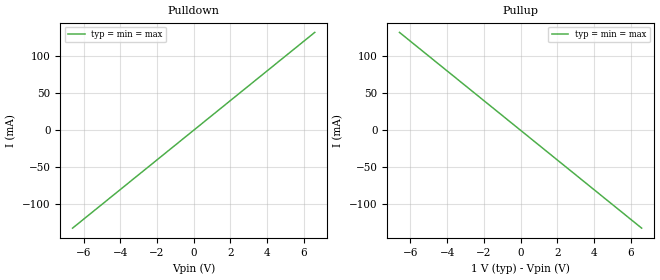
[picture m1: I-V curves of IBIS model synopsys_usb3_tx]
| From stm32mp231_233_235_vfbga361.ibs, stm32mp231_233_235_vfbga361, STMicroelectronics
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[Model] synopsys_usb3_tx
Model_type Output
C_comp 1.69p   1.72p   1.86p
Cref = 0
Vref = 0.5
Rref = 50
Vmeas = 0.5
[Temperature_Range] 25 125 -40
[Voltage Range] 1.0 1.0 1.0
[Algorithmic Model]
Executable Linux_GCC_64 synopsys_usb3_tx_ami_x64.so synopsys_usb3_tx_ami.ami
Executable Windows_cl_64 synopsys_usb3_tx_ami_x64.dll synopsys_usb3_tx_ami.ami
Executable Windows_cl_32 synopsys_usb3_tx_ami.dll synopsys_usb3_tx_ami.ami
[End Algorithmic Model]
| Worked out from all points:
|   slope of the pulldown table from 0 to 0.15 V, typ, clamps not added: 50 ohm
|   slope of the pullup table from 0 to 0.15 V, typ, clamps not added: 50 ohm
[Pulldown]
-6.6V     -132mA     -132mA     -132mA
0V        0A         0A         0A
6.6V      132mA      132mA      132mA
[Pullup]
-6.6V     132mA      132mA      132mA
0V        0A         0A         0A
6.6V      -132mA     -132mA     -132mA
[GND Clamp]
-6.6V     0A         0A         0A
0V        0A         0A         0A
6.6V      0A         0A         0A
[Power Clamp]
-6.6V     0A         0A         0A
0V        0A         0A         0A
6.6V      0A         0A         0A
[Ramp]
dV/dt_r 0.3/1.25p 0.3/1.25p 0.3/1.25p
dV/dt_f 0.3/1.25p 0.3/1.25p 0.3/1.25p
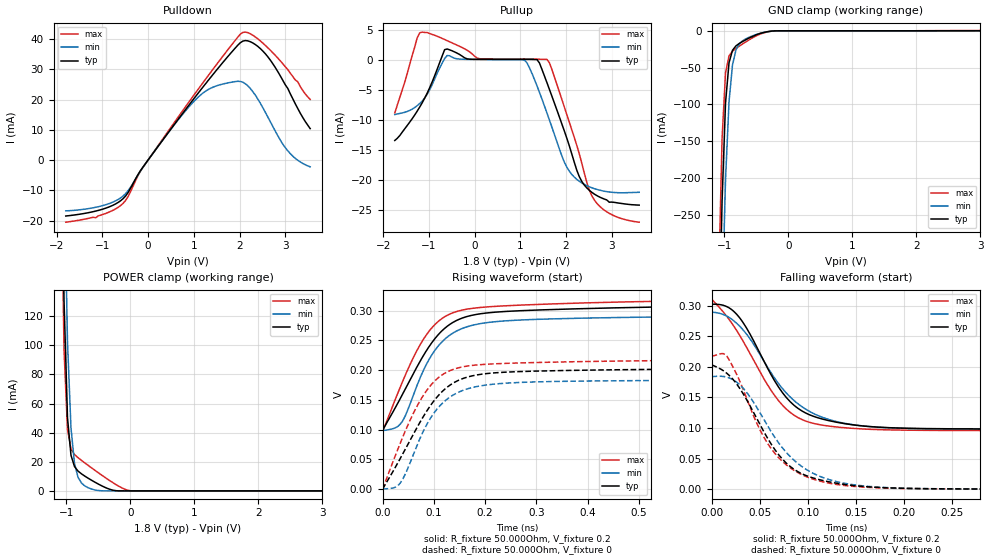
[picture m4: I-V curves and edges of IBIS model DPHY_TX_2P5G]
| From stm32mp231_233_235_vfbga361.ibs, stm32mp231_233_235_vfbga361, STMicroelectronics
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[Model] DPHY_TX_2P5G
Model_type   Output
Polarity   Non-Inverting
Enable   Active-High
C_comp 1.4pF   1.37pF   1.41pF
| This model is not intended for timing simulations.
| Warnings about Cref, Vref & Rref can be ignored
[Temperature Range]   25.000   -40.000   125.000
[Voltage Range]   1.800V   1.516V   2.030V
[GND Clamp Reference]   0.00V   0.00V   0.00V
[Pulldown Reference]   0.00V   0.00V   0.00V
[POWER Clamp Reference]   1.800V   1.516V   2.030V
[Pullup Reference]   1.800V   1.516V   2.030V
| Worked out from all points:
|   slope of the pulldown table from 0 to 0.27 V, typ, clamps not added: 48.6 ohm
|   slope of the pullup table from 0 to 0.27 V, typ, clamps not added: 40.7 kohm
|   GND clamp passes 1 mA (typ) near -0.31 V on its own axis
|   POWER clamp passes 1 mA (typ) near -0.31 V on its own axis
|   rising waveform, R_fixture 50.000Ohm, V_fixture 0.2: 20-80 % time 90.4ps typ, 71.9ps min, 79.7ps max; typ from 0.099 V to 0.31 V
|   rising waveform, R_fixture 50.000Ohm, V_fixture 0: 20-80 % time 87ps typ, 69.4ps min, 74.4ps max; typ from 0 V to 0.203 V
|   falling waveform, R_fixture 50.000Ohm, V_fixture 0.2: 20-80 % time 47.3ps typ, 55.3ps min, 50.3ps max; typ from 0.302 V to 0.098 V
|   falling waveform, R_fixture 50.000Ohm, V_fixture 0: 20-80 % time 48.9ps typ, 52.6ps min, 45ps max; typ from 0.203 V to 0 V
[GND Clamp]
-1.8V     -4.042A    -4.073A    -4.034A
-1.091V   -451.6mA   -607.8mA   -348.2mA
-1.036V   -231.6mA   -376.3mA   -146.6mA
-981.8mV  -97.78mA   -201.9mA   -57.02mA
-927.3mV  -43.35mA   -96.27mA   -34.12mA
-872.7mV  -26.43mA   -46.13mA   -27.69mA
-818.2mV  -20.42mA   -25.76mA   -23.97mA
-763.6mV  -17.02mA   -17.38mA   -20.69mA
-654.5mV  -11.72mA   -10.47mA   -14.49mA
-436.4mV  -3.482mA   -3.303mA   -4.29mA
-218.2mV  -146.9uA   -265.1uA   -132uA
3.545V    426.1nA    2.473uA    648.9uA
[Power Clamp]
-1.745V   4.178A     4.144A     4.305A
-1.091V   310.6mA    421.8mA    251.8mA
-1.036V   130.9mA    223.5mA    97.01mA
-981.8mV  50.29mA    102.3mA    42.42mA
-927.3mV  24.5mA     43.3mA     28.87mA
-872.7mV  16.75mA    18.99mA    25.02mA
-818.2mV  13.67mA    9.453mA    22.85mA
-709.1mV  10.1mA     3.359mA    19.17mA
-545.5mV  5.79mA     575.5uA    13.9mA
-327.3mV  1.19mA     3.793uA    7.229mA
-3uV      9.747nA    10.82nA    94.99uA
3.6V      -1.243uA   -14.78uA   -237.3nA
[Pulldown]
-1.8V     -18.49mA   -16.79mA   -20.54mA
-1.145V   -16.87mA   -15.61mA   -19.07mA
-545.5mV  -12.76mA   -11.88mA   -14.3mA
-163.6mV  -3.435mA   -3.542mA   -3.617mA
600mV     12.28mA    12.18mA    12.96mA
1.091V    22.02mA    20.73mA    23.3mA
1.527V    30.28mA    24.68mA    32.17mA
2.073V    39.32mA    25.73mA    42.18mA
2.291V    38.7mA     22.63mA    41.27mA
2.618V    34.15mA    14.25mA    37.13mA
3.055V    23.7mA     3.064mA    29.91mA
3.545V    10.4mA     -2.252mA   20.05mA
[Pullup]
-1.745V   -13.43mA   -9.108mA   -8.84mA
-1.2V     -7.861mA   -7.271mA   4.52mA
-654.5mV  1.717mA    221.3uA    3.412mA
109.1mV   108.7uA    79.91uA    207.6uA
1.091V    102.7uA    -16.32uA   159.1uA
1.364V    71.88uA    -4.288mA   132.1uA
1.582V    -3.769mA   -8.826mA   89.18uA
2.018V    -13.07mA   -17.9mA    -9.136mA
2.291V    -19.47mA   -20.24mA   -15.68mA
2.564V    -22.08mA   -21.32mA   -22.65mA
2.945V    -23.73mA   -22.02mA   -25.58mA
3.6V      -24.21mA   -22.07mA   -27.06mA
[Ramp]
R_load=50.000Ohm
dV/dt_r   120.00mV/52.400ps  113.564mV/80.000ps  130.791mV/52.000ps
dV/dt_f   120.00mV/46.300ps  112.106mV/62.000ps  129.869mV/46.000ps
[Rising waveform]
R_fixture=50.000Ohm
V_fixture=0.2
0s        98.93mV    98.23mV    96.1mV
24ps      135.4mV    102.7mV    148.9mV
38ps      157.8mV    113.1mV    178.6mV
60ps      194mV      157.8mV    221mV
80ps      225mV      200.1mV    252.3mV
112ps     262.8mV    244mV      284.2mV
150ps     285.7mV    268mV      299.8mV
206ps     296.3mV    280.1mV    306.3mV
308ps     301.1mV    285.5mV    310.5mV
1ns       310.1mV    291.9mV    319.4mV
[Rising waveform]
R_fixture=50.000Ohm
V_fixture=0
0s        -153uV     -19.38uV   -161.4uV
24ps      35.19mV    2.763mV    54.32mV
36ps      53.77mV    12.09mV    80.4mV
58ps      89.01mV    53.64mV    123.7mV
78ps      119.8mV    94.7mV     155.5mV
110ps     158.4mV    138.4mV    188mV
148ps     182.8mV    162.8mV    203.9mV
202ps     194.1mV    174.9mV    209.8mV
298ps     198.3mV    180.1mV    212.7mV
1ns       203mV      183.3mV    217.6mV
[Falling waveform]
R_fixture=50.000Ohm
V_fixture=0.2
0s        302.4mV    289.3mV    310.9mV
16ps      298.4mV    282.8mV    282.3mV
28ps      282.6mV    268.5mV    254.8mV
58ps      198.8mV    200.2mV    171.4mV
74ps      157.4mV    164.1mV    137mV
94ps      128mV      135mV      113.9mV
120ps     112.8mV    115mV      103.6mV
162ps     102.7mV    102.7mV    98.07mV
230ps     98.96mV    98.49mV    96.1mV
1ns       98.45mV    97.91mV    95.88mV
[Falling waveform]
R_fixture=50.000Ohm
V_fixture=0
0s        203.4mV    184mV      217.7mV
12ps      194mV      184.4mV    221.7mV
16ps      189.3mV    183.2mV    217.3mV
32ps      158.4mV    166.6mV    166.7mV
52ps      101mV      120.7mV    92.07mV
72ps      52.27mV    71.18mV    48.03mV
98ps      22.53mV    32.82mV    20.9mV
132ps     9.241mV    11.68mV    7.297mV
238ps     571.6uV    594.6uV    460.2uV
998ps     12.42uV    68.5uV     6.531uV
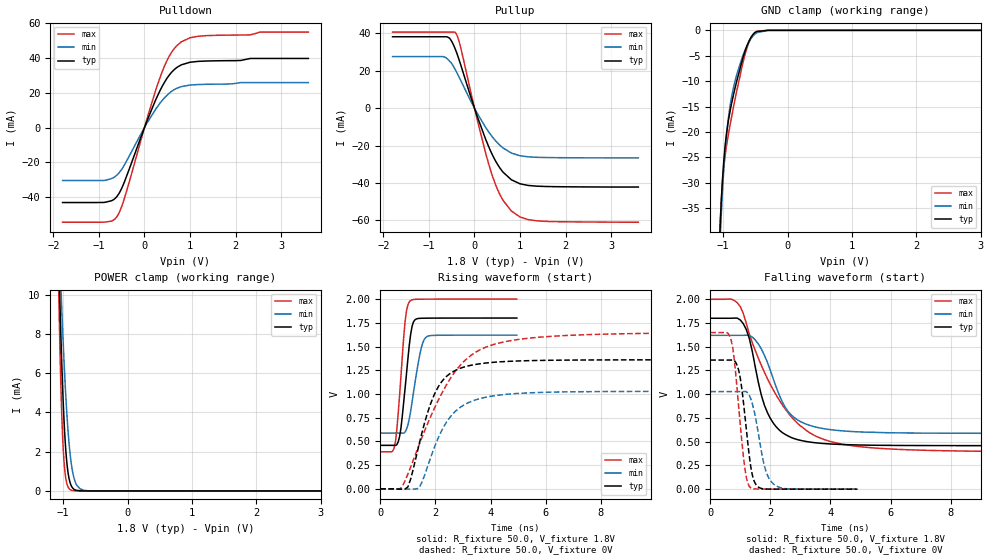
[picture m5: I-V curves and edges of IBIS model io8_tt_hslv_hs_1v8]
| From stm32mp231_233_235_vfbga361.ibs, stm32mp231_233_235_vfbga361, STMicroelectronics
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[Model]   io8_tt_hslv_hs_1v8
Model_type I/O
Polarity   Non-Inverting
Enable   Active-Low
| CAP_THRESHOLD on pad IOTT is "UDTCAPC" :
| Rising=30.0% of vddiov33m   Falling=70.0% of vddiov33m
| C_comp min and max val. don't necessarily correlate with the min and max pvt
| but are the smallest and greatest pad capacitance found.
| var   typ   min   max
C_comp   1.16096pF  1.09790pF  1.36394pF
|C_comp_pullup   764.88000fF  538.03000fF  521.00000fF
|C_comp_pulldown   396.07600fF  559.87040fF  842.94418fF
Vinl = 486.0mV
Vinh = 1.4V
Vmeas = 900.0mV   | Reference voltage for timing measurements
Cref  = 50.0pF   | Timing specification test load capacitance value
Rref  = 100.0MOhm   | Timing specification test load resistance value
Vref  = 900.0mV   | Timing specification test load voltage
[Model Spec]
| TIME_THRESHOLD on pin ZIV08M is "CMOS" :
| Rising=50.0% of vddv08m   Falling=50.0% of vddv08m
Vinl 675.70000mV 623.70000mV 735.70000mV
Vinh 1.12730V 1.01130V 1.24930V
| variable   typ   min   max
[Temperature Range] 25.0 125.0 -40.0
| variable   typ   min   max
[Voltage Range] 1.8V 1.62V 2.0V
| variable   typ   min   max
[POWER Clamp Reference] 1.8V 1.62V 2.0V
| variable   typ   min   max
[GND Clamp Reference] 0V 0V 0V
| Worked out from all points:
|   slope of the pulldown table from 0 to 0.27 V, typ, clamps not added: 15.6 ohm
|   slope of the pullup table from 0 to 0.27 V, typ, clamps not added: 14.9 ohm
|   GND clamp passes 1 mA (typ) near -0.55 V on its own axis
|   POWER clamp passes 1 mA (typ) near -0.93 V on its own axis
|   rising waveform, R_fixture 50.0, V_fixture 1.8V: 20-80 % time 277ps typ, 346ps min, 248ps max; typ from 0.458 V to 1.8 V
|   falling waveform, R_fixture 50.0, V_fixture 1.8V: 20-80 % time 697ps typ, 861ps min, 1.58ns max; typ from 1.8 V to 0.458 V
|   rising waveform, R_fixture 50.0, V_fixture 0V: 20-80 % time 883ps typ, 1.06ns min, 1.72ns max; typ from 0 V to 1.36 V
|   falling waveform, R_fixture 50.0, V_fixture 0V: 20-80 % time 296ps typ, 377ps min, 294ps max; typ from 1.36 V to 0 V
[POWER Clamp]
-1.8V     152.1mA    105.6mA    221.1mA
-1.07V    12.07mA    13.61mA    10.38mA
-1.05V    9.569mA    11.75mA    7.248mA
-1.03V    7.339mA    9.993mA    4.743mA
-1.01V    5.42mA     8.358mA    2.898mA
-990mV    3.841mA    6.859mA    1.662mA
-970mV    2.609mA    5.513mA    906.4uA
-940mV    1.358mA    3.806mA    344.1uA
-880mV    308.2uA    1.548mA    45.5uA
-790mV    28.46uA    298.9uA    2.106uA
-610mV    213nA      7.572uA    9.541nA
3.6V      0A         0A         0A
[GND Clamp]
-1.8V     -1.214A    -1.184A    -1.231A
-1.05V    -39.75mA   -42.57mA   -39.2mA
-1.04V    -36.64mA   -39.37mA   -36.3mA
-1.01V    -29.33mA   -31.48mA   -29.9mA
-970mV    -22.87mA   -23.87mA   -24.77mA
-920mV    -17.89mA   -17.43mA   -20.6mA
-870mV    -14.47mA   -13.19mA   -17.12mA
-790mV    -10.04mA   -8.766mA   -11.99mA
-650mV    -3.743mA   -3.579mA   -4.327mA
-570mV    -1.451mA   -1.665mA   -1.53mA
-490mV    -324.1uA   -556uA     -259.6uA
3.6V      61.92nA    2.591uA    17.99nA
| variable   typ   min   max
[Pullup Reference] 1.8V 1.62V 2.0V
| variable   typ   min   max
[Pulldown Reference] 0V 0V 0V
[Pullup]
-1.8V     38.22mA    27.62mA    40.72mA
-610mV    38.2mA     26.68mA    40.72mA
-520mV    36.51mA    24.52mA    40.72mA
-410mV    30.85mA    20.07mA    40.15mA
-310mV    23.77mA    15.24mA    33.09mA
70mV      -5.022mA   -3.131mA   -7.212mA
350mV     -22.69mA   -13.97mA   -32.92mA
570mV     -32.38mA   -20.06mA   -46.75mA
810mV     -38.27mA   -23.98mA   -54.98mA
1V        -40.44mA   -25.43mA   -58.16mA
1.37V     -41.7mA    -26.27mA   -60.24mA
3.6V      -42.17mA   -26.59mA   -60.97mA
[Pulldown]
-1.8V     -43.17mA   -30.47mA   -54.48mA
-870mV    -43.05mA   -30.42mA   -54.44mA
-700mV    -41.81mA   -29.1mA    -53.55mA
-600mV    -39.48mA   -27.21mA   -51.03mA
-440mV    -31.2mA    -21.48mA   -40.66mA
70mV      4.786mA    3.206mA    6.392mA
360mV     22.22mA    14.64mA    30.08mA
580mV     31.3mA     20.48mA    42.61mA
810mV     36.07mA    23.54mA    49.29mA
1.18V     38.05mA    24.73mA    52.5mA
2.54V     39.74mA    25.83mA    54.9mA
3.6V      39.74mA    25.83mA    54.9mA
[Ramp]
dV/dt_r 815.91777mV/880.26435ps 616.4936mV/1.06095ns 989.54584mV/1.71881ns
dV/dt_f 805.07502mV/690.74548ps 619.18802mV/857.58084ps 965.62558mV/1.58556ns
R_load = 50.0
| Removed startup time: 0s 0s 0s  .
| Removed end time: 4.95ns.
[Rising Waveform]
R_fixture   = 50.0
V_fixture   = 1.8V
V_fixture_min = 1.62V
V_fixture_max = 2.0V
0s        458.3mV    588.1mV    390.7mV
450ps     458.3mV    588.1mV    397.7mV
550ps     457.3mV    588.1mV    495.5mV
700ps     550.8mV    588.1mV    986.9mV
900ps     1.062V     598.8mV    1.765V
1.05ns    1.51V      735.5mV    1.97V
1.2ns     1.757V     1.008V     1.995V
1.45ns    1.797V     1.439V     1.999V
1.65ns    1.799V     1.596V     1.999V
4.95ns    1.8V       1.62V      2V
| Removed startup time: 0s 0s 0s  .
| Removed end time: 29.8ns.
[Falling Waveform]
R_fixture   = 50.0
V_fixture   = 1.8V
V_fixture_min = 1.62V
V_fixture_max = 2.0V
0s        1.8V       1.62V      2V
700ps     1.8V       1.62V      2.002V
1.1ns     1.743V     1.62V      1.851V
1.3ns     1.587V     1.62V      1.634V
1.8ns     886.5mV    1.412V     1.233V
2.3ns     621.5mV    989.6mV    936.2mV
2.6ns     558.8mV    815.1mV    800.5mV
3ns       514.2mV    712.3mV    666.3mV
4.5ns     469.1mV    611.5mV    468mV
29.8ns    458.3mV    588.1mV    390.7mV
| Removed startup time: 0s 0s 0s  .
| Removed end time: 29.9ns.
[Rising Waveform]
R_fixture   = 50.0
V_fixture   = 0V
V_fixture_min = 0V
V_fixture_max = 0V
0s        0V         0V         0V
700ps     -2.755mV   -7.882uV   -1.811mV
1ns       19.97mV    -1.924mV   156.6mV
1.4ns     460.5mV    8.603mV    458.1mV
1.8ns     877.5mV    308.1mV    744.3mV
2.4ns     1.185V     702.7mV    1.096V
3.3ns     1.303V     921.6mV    1.409V
4.6ns     1.343V     996.8mV    1.555V
10ns      1.36V      1.027V     1.639V
29.9ns    1.36V      1.027V     1.649V
| Removed startup time: 0s 0s 0s  .
| Removed end time: 4.9ns.
[Falling Waveform]
R_fixture   = 50.0
V_fixture   = 0V
V_fixture_min = 0V
V_fixture_max = 0V
0s        1.36V      1.027V     1.649V
700ps     1.36V      1.027V     1.563V
800ps     1.356V     1.027V     1.364V
1ns       1.167V     1.027V     674.5mV
1.15ns    781.3mV    1.029V     221.5mV
1.3ns     345.8mV    987.7mV    28.88mV
1.55ns    36.56mV    679.4mV    1.803mV
1.8ns     2.784mV    246.3mV    835.3uV
2.1ns     791.3uV    55.52mV    464.4uV
4.9ns     0V         0V         0V
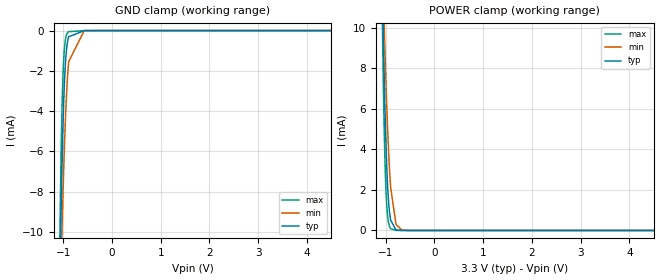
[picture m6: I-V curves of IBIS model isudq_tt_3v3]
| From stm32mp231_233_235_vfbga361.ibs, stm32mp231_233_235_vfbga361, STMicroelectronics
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[Model]   isudq_tt_3v3
Model_type Input
Polarity   Non-Inverting
Enable   Active-Low
| CAP_THRESHOLD on pad IOTT is "UDTCAPC" :
| Rising=30.0% of vddiov33m   Falling=70.0% of vddiov33m
| C_comp min and max val. don't necessarily correlate with the min and max pvt
| but are the smallest and greatest pad capacitance found.
| var   typ   min   max
C_comp   861.45000fF  853.44000fF  870.70500fF
|C_comp_pullup   394.94500fF  400.83500fF  393.08000fF
|C_comp_pulldown   466.50500fF  452.60500fF  477.62500fF
Vinl = 810.0mV
Vinh = 2.52V
[Model Spec]
| TIME_THRESHOLD on pin ZIV08M is "CMOS" :
| Rising=50.0% of vddv08m   Falling=50.0% of vddv08m
Vinl 1.19670V 872.70000mV 1.24570V
Vinh 1.29530V 1.04830V 1.42630V
| variable   typ   min   max
[Temperature Range] 25.0 125.0 -40.0
| variable   typ   min   max
[Voltage Range] 3.3V 2.7V 3.6V
| variable   typ   min   max
[POWER Clamp Reference] 3.3V 2.7V 3.6V
| variable   typ   min   max
[GND Clamp Reference] 0V 0V 0V
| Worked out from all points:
|   GND clamp passes 1 mA (typ) near -0.94 V on its own axis
|   POWER clamp passes 1 mA (typ) near -0.93 V on its own axis
[POWER Clamp]
-3.3V     559.5mA    317.6mA    1.064A
-1.07V    12.07mA    13.62mA    10.38mA
-1.06V    10.79mA    12.67mA    8.74mA
-1.05V    9.569mA    11.75mA    7.249mA
-1.03V    7.339mA    9.995mA    4.744mA
-1V       4.587mA    7.592mA    2.211mA
-980mV    3.182mA    6.168mA    1.234mA
-950mV    1.703mA    4.334mA    478uA
-900mV    514.3uA    2.138mA    89.97uA
-790mV    28.53uA    300uA      2.205uA
-670mV    1.17uA     27.81uA    97.85nA
6.6V      0A         0A         0A
[GND Clamp]
-3.3V     -657.7mA   -390.1mA   -1.178A
-1.07V    -12.53mA   -14.65mA   -10.34mA
-1.05V    -9.67mA    -12.44mA   -6.916mA
-1.03V    -7.182mA   -10.39mA   -4.31mA
-1.02V    -6.092mA   -9.425mA   -3.312mA
-1V       -4.24mA    -7.635mA   -1.866mA
-980mV    -2.822mA   -6.044mA   -1mA
-950mV    -1.424mA   -4.065mA   -373.4uA
-920mV    -674.1uA   -2.582mA   -138.7uA
-890mV    -308.9uA   -1.558mA   -54.7uA
-570mV    -2.454uA   -5.061uA   -2.524uA
6.6V      43.73nA    147.3nA    41.4nA
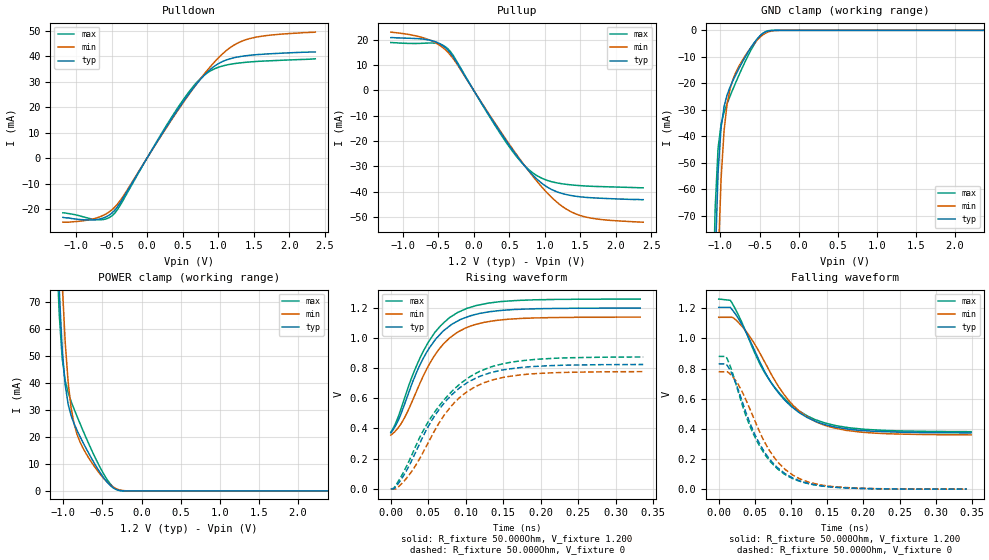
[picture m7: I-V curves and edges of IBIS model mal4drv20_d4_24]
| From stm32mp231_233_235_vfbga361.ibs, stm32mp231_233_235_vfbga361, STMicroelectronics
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[Model] mal4drv20_d4_24
Model_type   I/O
Polarity   Non-Inverting
Enable   Active-High
C_comp   1.838pF   1.835pF   1.848pF
C_comp_pullup   938.881fF   931.604fF   947.115fF
C_comp_pulldown 782.410fF   779.859fF   796.520fF
Vinh = 668.000mV
Vinl = 532.000mV
Vmeas = 600.000mV
Vref = 600.000mV
Rref = 50Ohms
Cref = 0pF
[Model Spec]
Vinh   668.000mV   638.000mV   698.000mV
Vinl   532.000mV   502.000mV   562.000mV
Vmeas   600.000mV   570.000mV   630.000mV
Vref   600.000mV   570.000mV   630.000mV
D_overshoot_ampl_h 0.24 NA   NA
D_overshoot_ampl_l 0.24 NA   NA
D_overshoot_area_l 300.000m NA   NA
D_overshoot_area_h 300.000m NA   NA
[Receiver Thresholds]
Vth = 600.000mV
Vth_min = 570.000mV
Vth_max = 630.000mV
Vinh_ac = 68.000mV
Vinh_dc = 68.000mV
Vinl_ac = -68.000mV
Vinl_dc = -68.000mV
Tslew_ac = 5.000ns
Threshold_sensitivity = 0.5
Reference_supply Pullup_ref
[Temperature Range]   25.000   125.000   -40.000
[Voltage Range]   1.200V   1.140V   1.260V
[GND Clamp Reference]   0.00V   0.00V   0.00V
[C Comp Corner]
| variable   typ   min   max
C_comp 1.848pF   1.838pF   1.835pF
C_comp_pullup 938.881fF   947.115fF   931.604fF
C_comp_pulldown 779.859fF   796.520fF   782.410fF
[Pulldown Reference]   0.00V   0.00V   0.00V
[POWER Clamp Reference]   1.200V   1.140V   1.260V
[Pullup Reference]   1.200V   1.140V   1.260V
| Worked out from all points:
|   slope of the pulldown table from 0 to 0.18 V, typ, clamps not added: 22 ohm
|   slope of the pullup table from 0 to 0.18 V, typ, clamps not added: 22.2 ohm
|   GND clamp passes 1 mA (typ) near -0.45 V on its own axis
|   POWER clamp passes 1 mA (typ) near -0.35 V on its own axis
|   rising waveform, R_fixture 50.000Ohm, V_fixture 1.200: 20-80 % time 50.8ps typ, 52.3ps min, 51.6ps max; typ from 0.371 V to 1.2 V
|   rising waveform, R_fixture 50.000Ohm, V_fixture 0: 20-80 % time 63.8ps typ, 62.8ps min, 69.8ps max; typ from -0.001 V to 0.825 V
|   falling waveform, R_fixture 50.000Ohm, V_fixture 1.200: 20-80 % time 64.7ps typ, 64.9ps min, 66.6ps max; typ from 1.21 V to 0.373 V
|   falling waveform, R_fixture 50.000Ohm, V_fixture 0: 20-80 % time 49.8ps typ, 51.7ps min, 49.2ps max; typ from 0.831 V to 0 V
[GND Clamp]
-1.184V   -365mA     -429.3mA   -336.5mA
-1.107V   -152.4mA   -215.7mA   -121.1mA
-1.069V   -88.87mA   -140.5mA   -67.62mA
-1.031V   -53.54mA   -88.39mA   -44.48mA
-992.7mV  -36.7mA    -56.18mA   -35.42mA
-954.6mV  -28.78mA   -37.93mA   -30.92mA
-916.4mV  -24.43mA   -27.89mA   -27.7mA
-840mV    -18.89mA   -18.42mA   -22.12mA
-763.6mV  -14.38mA   -13.51mA   -16.88mA
-572.7mV  -4.818mA   -5.067mA   -5.477mA
-458.2mV  -1.146mA   -1.695mA   -1.103mA
2.367V    25.44nA    625nA      8.401nA
[Power Clamp]
-1.167V   197.6mA    234.2mA    183.1mA
-1.091V   108mA      144mA      94.42mA
-1.053V   75.21mA    107.2mA    65.93mA
-1.015V   52.65mA    77.42mA    49.33mA
-976.4mV  39.37mA    55.31mA    41.02mA
-938.2mV  32.15mA    40.29mA    36.48mA
-900mV    27.91mA    30.75mA    33.22mA
-823.6mV  22.42mA    20.91mA    27.62mA
-632.7mV  11.76mA    10.36mA    14.83mA
-365.4mV  1.178mA    1.496mA    1.508mA
-212.7mV  14.35uA    76.22uA    9.056uA
2.384V    -16.74nA   -562.7nA   -5.86nA
[Pulldown]
-1.184V   -23.3mA    -25.2mA    -21.5mA
-725.5mV  -24.22mA   -23.67mA   -24.16mA
-572.7mV  -23.05mA   -21.87mA   -23.88mA
-458.2mV  -20.62mA   -19.39mA   -21.77mA
-343.6mV  -16.07mA   -15.35mA   -16.92mA
420mV     18.52mA    18.15mA    19.25mA
687.3mV   28.79mA    28.76mA    29.36mA
878.2mV   34.54mA    35.52mA    34.04mA
1.145V    38.82mA    42.9mA     36.72mA
1.375V    40.15mA    46.36mA    37.59mA
1.68V     40.89mA    48.13mA    38.16mA
2.367V    41.7mA     49.5mA     39mA
[Pullup]
-1.167V   20.9mA     23.09mA    18.96mA
-594.5mV  19.74mA    19.63mA    18.78mA
-480mV    18.52mA    17.87mA    18.36mA
-365.4mV  16.04mA    15.16mA    16.51mA
-250.9mV  11.58mA    11.05mA    12.1mA
283.6mV   -12.64mA   -12.29mA   -13.12mA
550.9mV   -23.72mA   -23.31mA   -24.27mA
780mV     -31.93mA   -32.08mA   -31.46mA
1.009V    -37.76mA   -39.8mA    -35.31mA
1.276V    -41mA      -46.45mA   -37.04mA
1.505V    -42.09mA   -49.52mA   -37.66mA
2.384V    -43.2mA    -52.1mA    -38.5mA
[Ramp]
R_load=50.000Ohm
dV/dt_r   495.900mV/58.500ps  467.789mV/58.500ps  526.500mV/61.500ps
dV/dt_f   495.900mV/58.500ps  467.789mV/59.500ps  526.500mV/58.500ps
[Rising waveform]
R_fixture=50.000Ohm
V_fixture=1.200
V_fixture_min=1.140
V_fixture_max=1.260
0s        371mV      355.7mV    374.9mV
8ps       434.2mV    393.5mV    452.7mV
18ps      556.5mV    468.2mV    597.7mV
33ps      757.3mV    632.5mV    802mV
49ps      915.7mV    805.8mV    964.1mV
69ps      1.043V     954.7mV    1.096V
90ps      1.116V     1.042V     1.173V
114ps     1.159V     1.093V     1.217V
158ps     1.188V     1.127V     1.247V
333ps     1.2V       1.14V      1.26V
[Rising waveform]
R_fixture=50.000Ohm
V_fixture=0
0s        -1.388mV   -3.295mV   -3.211mV
10ps      34.41mV    11.79mV    48.86mV
27ps      177.4mV    108.4mV    213.2mV
46ps      377mV      268.9mV    411.2mV
64ps      522.6mV    433.3mV    546.7mV
90ps      662.1mV    597mV      685.9mV
118ps     745.5mV    689.5mV    778.3mV
152ps     791.1mV    741.5mV    832.5mV
191ps     812.1mV    763.9mV    858.7mV
337ps     825.2mV    777.8mV    875.1mV
[Falling waveform]
R_fixture=50.000Ohm
V_fixture=1.200
V_fixture_min=1.140
V_fixture_max=1.260
0s        1.206V     1.14V      1.261V
16ps      1.206V     1.14V      1.253V
31ps      1.102V     1.087V     1.117V
57ps      842.3mV    901.9mV    829.1mV
70ps      724.9mV    785.5mV    723.8mV
96ps      568mV      592.5mV    576.8mV
122ps     475.8mV    480.9mV    487.1mV
147ps     428mV      422.9mV    439mV
189ps     393mV      381.8mV    402.8mV
349ps     373.4mV    360.2mV    381.6mV
[Falling waveform]
R_fixture=50.000Ohm
V_fixture=0
0s        831.3mV    778.6mV    880.7mV
10ps      831.3mV    778.6mV    880.7mV
23ps      711.4mV    723.5mV    710.1mV
41ps      465.2mV    555.3mV    443.8mV
57ps      296.8mV    374.9mV    281.8mV
76ps      168.1mV    214.4mV    159.1mV
99ps      82.01mV    105mV      77.43mV
125ps     36.59mV    45.78mV    35.6mV
162ps     12.39mV    15.18mV    12.25mV
343ps     145.3uV    246.9uV    115.1uV
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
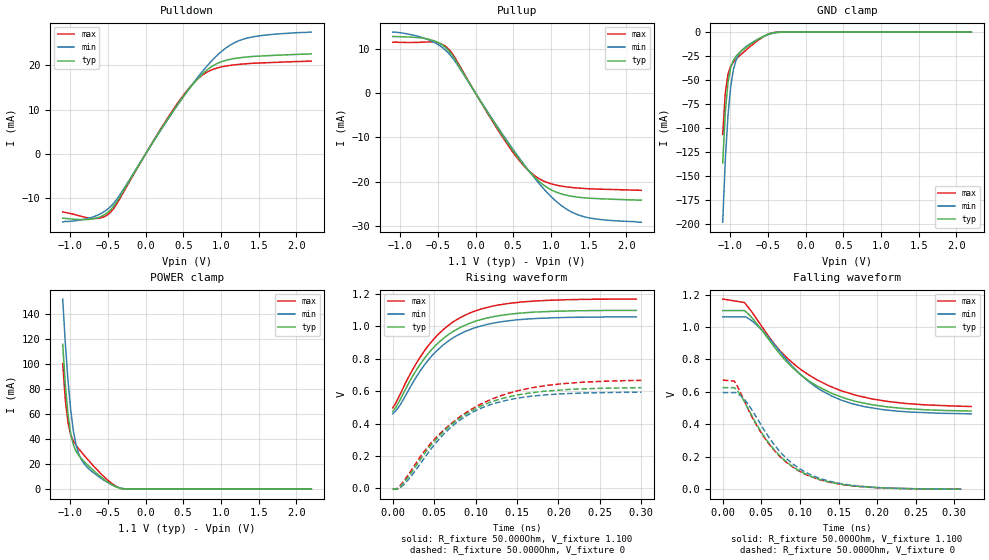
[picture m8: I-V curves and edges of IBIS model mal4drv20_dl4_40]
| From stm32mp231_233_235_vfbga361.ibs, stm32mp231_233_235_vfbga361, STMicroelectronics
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[Model] mal4drv20_dl4_40
Model_type   I/O
Polarity   Non-Inverting
Enable   Active-High
C_comp   1.837pF   1.837pF   1.849pF
C_comp_pullup   942.491fF   934.703fF   950.576fF
C_comp_pulldown 782.742fF   781.933fF   799.826fF
Vinh = 366.000mV
Vinl = 246.000mV
Vmeas = 306.000mV
Vref = 0.00V
Rref = 50Ohms
Cref = 0pF
[Model Spec]
Vinh   366.000mV   354.000mV   385.000mV
Vinl   246.000mV   234.000mV   265.000mV
Vmeas   306.000mV   294.000mV   325.000mV
Vref   0.00V   0.00V   0.00V
D_overshoot_ampl_h 0.3 NA   NA
D_overshoot_ampl_l 0.3 NA   NA
D_overshoot_area_l 100.000m NA   NA
D_overshoot_area_h 100.000m NA   NA
[Receiver Thresholds]
Vth = 306.000mV
Vth_min = 294.000mV
Vth_max = 325.000mV
Vinh_ac = 600.000mV
Vinh_dc = 600.000mV
Vinl_ac = -600.000mV
Vinl_dc = -600.000mV
Tslew_ac = 5.000ns
Threshold_sensitivity = 0.5
Reference_supply Pullup_ref
[Temperature Range]   25.000   125.000   -40.000
[Voltage Range]   1.100V   1.060V   1.170V
[GND Clamp Reference]   0.00V   0.00V   0.00V
[C Comp Corner]
| variable   typ   min   max
C_comp 1.849pF   1.837pF   1.837pF
C_comp_pullup 942.491fF   950.576fF   934.703fF
C_comp_pulldown 781.933fF   799.826fF   782.742fF
[Pulldown Reference]   0.00V   0.00V   0.00V
[POWER Clamp Reference]   1.100V   1.060V   1.170V
[Pullup Reference]   1.100V   1.060V   1.170V
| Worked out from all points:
|   slope of the pulldown table from 0 to 0.165 V, typ, clamps not added: 36.6 ohm
|   slope of the pullup table from 0 to 0.165 V, typ, clamps not added: 36.6 ohm
|   GND clamp passes 1 mA (typ) near -0.45 V on its own axis
|   POWER clamp passes 1 mA (typ) near -0.36 V on its own axis
|   rising waveform, R_fixture 50.000Ohm, V_fixture 1.100: 20-80 % time 60.5ps typ, 59.7ps min, 61.4ps max; typ from 0.475 V to 1.1 V
|   rising waveform, R_fixture 50.000Ohm, V_fixture 0: 20-80 % time 76.1ps typ, 69.8ps min, 86.6ps max; typ from -0.004 V to 0.622 V
|   falling waveform, R_fixture 50.000Ohm, V_fixture 1.100: 20-80 % time 83.3ps typ, 78.9ps min, 89.9ps max; typ from 1.1 V to 0.482 V
|   falling waveform, R_fixture 50.000Ohm, V_fixture 0: 20-80 % time 62.6ps typ, 62.6ps min, 62.7ps max; typ from 0.626 V to 0.001 V
[GND Clamp]
-1.099V   -136.3mA   -197.9mA   -106.5mA
-1.064V   -82.47mA   -132mA     -62.93mA
-1.028V   -52.05mA   -85.75mA   -43.61mA
-992.7mV  -36.88mA   -56.43mA   -35.5mA
-957.3mV  -29.36mA   -39.14mA   -31.26mA
-921.8mV  -25.1mA    -29.22mA   -28.2mA
-886.4mV  -22.16mA   -23.33mA   -25.51mA
-850.9mV  -19.73mA   -19.54mA   -22.95mA
-780mV    -15.43mA   -14.59mA   -18.04mA
-531.8mV  -3.288mA   -3.748mA   -3.604mA
-390mV    -251.1uA   -613.4uA   -163.8uA
2.198V    42.3nA     621.2nA    4.643nA
[Power Clamp]
-1.098V   115.5mA    151.6mA    100.1mA
-1.063V   83.06mA    116mA      70.82mA
-1.027V   59.24mA    86.19mA    52.7mA
-991.8mV  44.02mA    63.02mA    43.29mA
-956.4mV  35.26mA    46.38mA    38.3mA
-920.9mV  30.19mA    35.27mA    34.98mA
-885.5mV  26.87mA    28.15mA    32.19mA
-850mV    24.29mA    23.52mA    29.6mA
-672.7mV  13.97mA    12.28mA    17.45mA
-424.5mV  2.786mA    2.91mA     3.554mA
-282.7mV  160.9uA    380.1uA    143.1uA
2.199V    -14.13nA   -533.6nA   -2.884nA
[Pulldown]
-1.099V   -14.5mA    -15.4mA    -13.1mA
-673.6mV  -14.57mA   -14.07mA   -14.56mA
-567.3mV  -13.93mA   -13.21mA   -14.29mA
-460.9mV  -12.55mA   -11.8mA    -13.1mA
-319.1mV  -9.034mA   -8.676mA   -9.41mA
106.4mV   2.925mA    2.85mA     3.032mA
425.4mV   11.18mA    11.07mA    11.47mA
673.6mV   16.62mA    16.9mA     16.65mA
886.4mV   19.82mA    21.18mA    19.04mA
1.099V    21.27mA    24.32mA    19.93mA
1.312V    21.84mA    25.98mA    20.32mA
2.198V    22.6mA     27.5mA     20.96mA
[Pullup]
-1.098V   12.8mA     13.8mA     11.5mA
-637.3mV  12.25mA    12.17mA    11.56mA
-495.5mV  11.44mA    10.98mA    11.35mA
-389.1mV  10.18mA    9.569mA    10.47mA
-282.7mV  7.906mA    7.46mA     8.289mA
213.6mV   -5.807mA   -5.608mA   -6.054mA
532.7mV   -13.83mA   -13.56mA   -14.2mA
745.5mV   -18.33mA   -18.41mA   -18.17mA
958.2mV   -21.44mA   -22.64mA   -20.27mA
1.171V    -22.96mA   -25.84mA   -21.12mA
1.384V    -23.59mA   -27.68mA   -21.51mA
2.199V    -24.2mA    -29.2mA    -21.99mA
[Ramp]
R_load=50.000Ohm
dV/dt_r   373.770mV/69.500ps  358.108mV/66.000ps  401.010mV/75.000ps
dV/dt_f   373.770mV/74.500ps  358.109mV/72.000ps  401.010mV/78.500ps
[Rising waveform]
R_fixture=50.000Ohm
V_fixture=1.100
V_fixture_min=1.060
V_fixture_max=1.170
0s        474.8mV    461.2mV    497.6mV
9ps       548.7mV    515.7mV    582.6mV
25ps      701.3mV    659.3mV    742.3mV
45ps      845.3mV    805.2mV    894.9mV
59ps      917mV      877.6mV    970.9mV
70ps      959.4mV    920.2mV    1.018V
93ps      1.019V     980.5mV    1.083V
119ps     1.058V     1.018V     1.124V
155ps     1.083V     1.043V     1.151V
294ps     1.099V     1.059V     1.169V
[Rising waveform]
R_fixture=50.000Ohm
V_fixture=0
0s        -3.967mV   -2.721mV   -4.333mV
6ps       -3.967mV   -2.721mV   536.5uV
14ps      38.92mV    26.78mV    49.42mV
40ps      226.9mV    201.3mV    242.1mV
62ps      353.9mV    337.3mV    363.1mV
86ps      451.2mV    439.1mV    459.9mV
114ps     524.9mV    510.4mV    539.2mV
151ps     577.3mV    557.9mV    603.4mV
185ps     600.9mV    577.8mV    635.4mV
300ps     622.1mV    594.2mV    667.2mV
[Falling waveform]
R_fixture=50.000Ohm
V_fixture=1.100
V_fixture_min=1.060
V_fixture_max=1.170
0s        1.101V     1.062V     1.172V
28ps      1.101V     1.062V     1.151V
36ps      1.067V     1.044V     1.104V
53ps      965.8mV    970.3mV    985.9mV
82ps      790.2mV    803mV      814.5mV
110ps     673.4mV    668.2mV    709mV
136ps     602.3mV    586.8mV    640.8mV
166ps     550.2mV    529.6mV    588.3mV
202ps     515mV      494.1mV    549.9mV
322ps     482.1mV    464.7mV    509.9mV
[Falling waveform]
R_fixture=50.000Ohm
V_fixture=0
0s        626.1mV    595.9mV    672.7mV
15ps      626.1mV    595.9mV    666.4mV
25ps      565.8mV    569.2mV    576.1mV
43ps      407.6mV    448.8mV    401.4mV
64ps      259.4mV    291.5mV    254.4mV
84ps      163.8mV    183.8mV    159.8mV
107ps     94.78mV    105.9mV    91.99mV
140ps     41.98mV    47.27mV    41.91mV
174ps     18.23mV    20.42mV    18.47mV
309ps     709.6uV    808.8uV    736.7uV
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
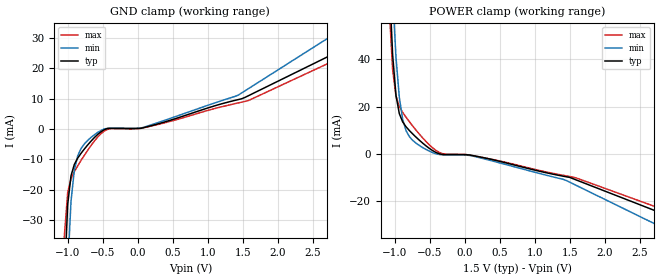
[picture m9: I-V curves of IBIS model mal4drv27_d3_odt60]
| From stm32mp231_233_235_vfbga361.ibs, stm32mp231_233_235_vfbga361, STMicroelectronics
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[Model] mal4drv27_d3_odt60
Model_type   Input
Polarity   Non-Inverting
Enable   Active-High
C_comp   1.765pF   1.636pF   1.804pF
C_comp_power_clamp   902.800fF   823.138fF   926.798fF
C_comp_gnd_clamp 730.097fF   713.943fF   741.180fF
Vinh = 885.000mV
Vinl = 615.000mV
[Model Spec]
D_overshoot_ampl_h 0.4 NA   NA
D_overshoot_ampl_l 0.4 NA   NA
D_overshoot_area_l 100.000m NA   NA
D_overshoot_area_h 100.000m NA   NA
[Receiver Thresholds]
Vth = 750.000mV
Vth_min = 713.000mV
Vth_max = 788.000mV
Vinh_ac = 135.000mV
Vinh_dc = 100.000mV
Vinl_ac = -135.000mV
Vinl_dc = -100.000mV
Tslew_ac = 5.000ns
Threshold_sensitivity = 0.5
Reference_supply Power_clamp_ref
[Temperature Range]   25.000   125.000   -40.000
[Voltage Range]   1.500V   1.425V   1.575V
[GND Clamp Reference]   0.00V   0.00V   0.00V
[C Comp Corner]
| variable   typ   min   max
C_comp 1.765pF   1.636pF   1.804pF
C_comp_pullup 902.800fF   823.138fF   926.798fF
C_comp_pulldown 730.097fF   713.943fF   741.180fF
[POWER Clamp Reference]   1.500V   1.425V   1.575V
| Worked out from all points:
|   GND clamp passes 1 mA (typ) near -0.53 V on its own axis
|   POWER clamp passes 1 mA (typ) near -0.43 V on its own axis
[GND Clamp]
-1.48V    -1.345A    -1.357A    -1.356A
-1.05V    -50.59mA   -90.43mA   -35.25mA
-1.002V   -24.76mA   -46.2mA    -20.87mA
-954.6mV  -15.35mA   -23.73mA   -16.37mA
-906.8mV  -11.62mA   -13.5mA    -14.01mA
-859.1mV  -9.564mA   -8.822mA   -12.1mA
-715.9mV  -5.214mA   -3.725mA   -6.961mA
-477.3mV  -195.1uA   59.89uA    -604.1uA
47.73mV   264.3uA    333.3uA    243.4uA
1.432V    9.675mA    11.13mA    8.584mA
1.575V    10.91mA    13.22mA    9.323mA
2.959V    26.57mA    33.44mA    24.15mA
[Power Clamp]
-1.459V   558.5mA    577mA      556.1mA
-1.077V   73.12mA    104.6mA    60.99mA
-1.03V    42.14mA    67.76mA    35.87mA
-981.8mV  24.84mA    40.95mA    24.59mA
-934.1mV  17.12mA    24.05mA    20.13mA
-886.4mV  13.64mA    14.75mA    17.65mA
-790.9mV  9.994mA    7.42mA     13.73mA
-647.7mV  5.884mA    3.653mA    8.461mA
-313.6mV  -185.9uA   -265.7uA   184.8uA
115.9mV   -618.4uA   -801uA     -632.3uA
1.405V    -9.31mA    -10.63mA   -8.937mA
2.98V     -26.89mA   -33.28mA   -24.95mA
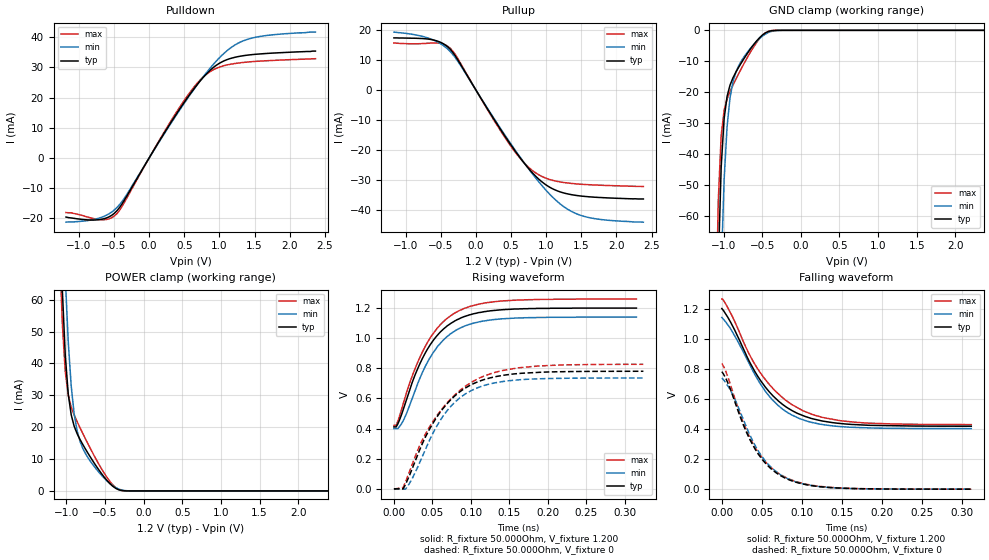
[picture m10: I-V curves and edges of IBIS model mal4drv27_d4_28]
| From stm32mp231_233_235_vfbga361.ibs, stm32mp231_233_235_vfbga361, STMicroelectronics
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[Model] mal4drv27_d4_28
Model_type   I/O
Polarity   Non-Inverting
Enable   Active-High
C_comp   1.656pF   1.652pF   1.661pF
C_comp_pullup   829.373fF   822.555fF   836.725fF
C_comp_pulldown 737.416fF   735.607fF   748.448fF
Vinh = 829.000mV
Vinl = 714.000mV
Vmeas = 771.000mV
Vref = 1.200V
Rref = 50Ohms
Cref = 0pF
[Model Spec]
Vinh   829.000mV   790.000mV   868.000mV
Vinl   714.000mV   675.000mV   753.000mV
Vmeas   771.000mV   733.000mV   810.000mV
Vref   1.200V   1.140V   1.260V
D_overshoot_ampl_h 0.24 NA   NA
D_overshoot_ampl_l 0.24 NA   NA
D_overshoot_area_l 300.000m NA   NA
D_overshoot_area_h 300.000m NA   NA
[Receiver Thresholds]
Vth = 771.000mV
Vth_min = 733.000mV
Vth_max = 810.000mV
Vinh_ac = 68.000mV
Vinh_dc = 68.000mV
Vinl_ac = -68.000mV
Vinl_dc = -68.000mV
Tslew_ac = 5.000ns
Threshold_sensitivity = 0.5
Reference_supply Pullup_ref
[Temperature Range]   25.000   125.000   -40.000
[Voltage Range]   1.200V   1.140V   1.260V
[GND Clamp Reference]   0.00V   0.00V   0.00V
[C Comp Corner]
| variable   typ   min   max
C_comp 1.661pF   1.656pF   1.652pF
C_comp_pullup 829.373fF   836.725fF   822.555fF
C_comp_pulldown 735.607fF   748.448fF   737.416fF
[Pulldown Reference]   0.00V   0.00V   0.00V
[POWER Clamp Reference]   1.200V   1.140V   1.260V
[Pullup Reference]   1.200V   1.140V   1.260V
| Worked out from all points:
|   slope of the pulldown table from 0 to 0.18 V, typ, clamps not added: 26 ohm
|   slope of the pullup table from 0 to 0.18 V, typ, clamps not added: 26.2 ohm
|   GND clamp passes 1 mA (typ) near -0.47 V on its own axis
|   POWER clamp passes 1 mA (typ) near -0.37 V on its own axis
|   rising waveform, R_fixture 50.000Ohm, V_fixture 1.200: 20-80 % time 45.6ps typ, 45ps min, 47.3ps max; typ from 0.411 V to 1.2 V
|   rising waveform, R_fixture 50.000Ohm, V_fixture 0: 20-80 % time 55.2ps typ, 51ps min, 63.7ps max; typ from 0 V to 0.781 V
|   falling waveform, R_fixture 50.000Ohm, V_fixture 1.200: 20-80 % time 55.9ps typ, 52.9ps min, 61.1ps max; typ from 1.2 V to 0.418 V
|   falling waveform, R_fixture 50.000Ohm, V_fixture 0: 20-80 % time 44ps typ, 44.4ps min, 44.7ps max; typ from 0.781 V to 0 V
[GND Clamp]
-1.184V   -313.6mA   -372.3mA   -285.9mA
-1.107V   -133mA     -190.9mA   -103.4mA
-1.069V   -76.66mA   -125mA     -55.43mA
-1.031V   -44.19mA   -77.99mA   -34.02mA
-992.7mV  -28.51mA   -48.19mA   -25.88mA
-954.6mV  -21.35mA   -31.1mA    -22.21mA
-916.4mV  -17.7mA    -21.78mA   -19.79mA
-878.2mV  -15.35mA   -16.61mA   -17.73mA
-801.8mV  -11.82mA   -11.34mA   -13.9mA
-610.9mV  -4.628mA   -4.618mA   -5.371mA
-458.2mV  -822.8uA   -1.198mA   -809uA
2.367V    18.95nA    454.6nA    6.243nA
[Power Clamp]
-1.167V   171.5mA    206.4mA    156.1mA
-1.091V   92.44mA    126.6mA    77.99mA
-1.053V   63.02mA    93.75mA    52.4mA
-1.015V   42.49mA    66.9mA     37.37mA
-976.4mV  30.34mA    46.72mA    30.02mA
-938.2mV  23.88mA    32.9mA     26.3mA
-900mV    20.31mA    24.15mA    23.84mA
-823.6mV  16.11mA    15.49mA    19.79mA
-747.3mV  12.87mA    11.46mA    16.02mA
-518.2mV  4.545mA    4.187mA    5.836mA
-365.4mV  856.5uA    1.078mA    1.107mA
2.384V    -12.74nA   -415.5nA   -4.625nA
[Pulldown]
-1.184V   -19.6mA    -21.3mA    -18.1mA
-725.5mV  -20.5mA    -20.03mA   -20.4mA
-572.7mV  -19.55mA   -18.53mA   -20.2mA
-458.2mV  -17.5mA    -16.43mA   -18.44mA
-343.6mV  -13.63mA   -13.01mA   -14.36mA
114.5mV   4.437mA    4.296mA    4.648mA
458.2mV   17.04mA    16.7mA     17.66mA
687.3mV   24.4mA     24.34mA    24.85mA
878.2mV   29.26mA    30.04mA    28.75mA
1.145V    32.87mA    36.22mA    30.99mA
1.375V    33.99mA    39.1mA     31.72mA
2.367V    35.4mA     41.7mA     32.88mA
[Pullup]
-1.167V   17.4mA     19.34mA    15.7mA
-632.7mV  16.85mA    16.95mA    15.69mA
-480mV    15.67mA    15.13mA    15.44mA
-365.4mV  13.6mA     12.86mA    13.95mA
-250.9mV  9.831mA    9.382mA    10.24mA
283.6mV   -10.73mA   -10.43mA   -11.1mA
550.9mV   -20.12mA   -19.79mA   -20.48mA
780mV     -27.02mA   -27.23mA   -26.43mA
1.009V    -31.87mA   -33.77mA   -29.57mA
1.276V    -34.55mA   -39.38mA   -30.98mA
1.505V    -35.45mA   -41.97mA   -31.5mA
2.384V    -36.4mA    -44.16mA   -32.24mA
[Ramp]
R_load=50.000Ohm
dV/dt_r   468.810mV/51.000ps  442.079mV/49.000ps  497.520mV/56.500ps
dV/dt_f   468.810mV/51.000ps  442.079mV/49.500ps  497.520mV/54.000ps
[Rising waveform]
R_fixture=50.000Ohm
V_fixture=1.200
V_fixture_min=1.140
V_fixture_max=1.260
0s        411.2mV    399.7mV    421.6mV
3ps       411.2mV    399.7mV    421.6mV
12ps      524.7mV    451.2mV    564mV
26ps      736.7mV    632.1mV    779.1mV
42ps      913.8mV    825.5mV    957.9mV
63ps      1.054V     981.9mV    1.104V
84ps      1.127V     1.062V     1.181V
109ps     1.169V     1.107V     1.225V
140ps     1.189V     1.129V     1.247V
315ps     1.2V       1.14V      1.26V
[Rising waveform]
R_fixture=50.000Ohm
V_fixture=0
0s        -153uV     -2.382mV   -1.769mV
12ps      -153uV     -2.382mV   9.177mV
19ps      72.99mV    25.68mV    97.34mV
38ps      312.1mV    228.5mV    335mV
63ps      528.1mV    476.8mV    534.2mV
84ps      638mV      597.2mV    646.1mV
109ps     710.9mV    671.9mV    730.8mV
140ps     752.5mV    711.5mV    784.7mV
177ps     770.9mV    728.2mV    811.8mV
324ps     780.6mV    735.9mV    826.9mV
[Falling waveform]
R_fixture=50.000Ohm
V_fixture=1.200
V_fixture_min=1.140
V_fixture_max=1.260
0s        1.2V       1.141V     1.263V
3ps       1.179V     1.124V     1.247V
12ps      1.099V     1.056V     1.16V
35ps      842.1mV    825.3mV    889.1mV
53ps      687.7mV    661.3mV    737.7mV
75ps      566.9mV    535.6mV    612.5mV
98ps      496mV      467.6mV    529.9mV
126ps     452.5mV    429mV      476.5mV
161ps     430.5mV    411.3mV    446.9mV
312ps     418.2mV    402.4mV    429mV
[Falling waveform]
R_fixture=50.000Ohm
V_fixture=0
0s        780.7mV    738.4mV    835.6mV
6ps       724.6mV    698.6mV    768.6mV
15ps      600.6mV    612.7mV    623mV
29ps      400.2mV    433.7mV    415mV
42ps      263mV      286.7mV    274.4mV
58ps      153.2mV    164.6mV    161.8mV
81ps      69.19mV    72.9mV     74.62mV
106ps     29.08mV    29.62mV    32.09mV
139ps     9.26mV     9.094mV    10.69mV
312ps     25.7uV     21.98uV    33.94uV
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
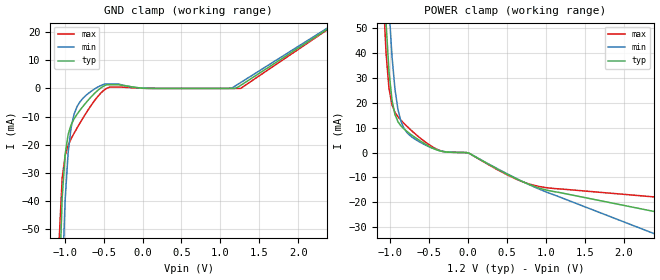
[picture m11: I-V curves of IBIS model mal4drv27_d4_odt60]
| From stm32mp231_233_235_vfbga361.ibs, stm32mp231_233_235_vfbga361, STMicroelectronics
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[Model] mal4drv27_d4_odt60
Model_type   Input
Polarity   Non-Inverting
Enable   Active-High
C_comp   1.968pF   1.724pF   2.024pF
C_comp_power_clamp   960.943fF   809.272fF   985.834fF
C_comp_gnd_clamp 863.816fF   819.972fF   885.457fF
Vinh = 848.000mV
Vinl = 733.000mV
[Model Spec]
D_overshoot_ampl_h 0.24 NA   NA
D_overshoot_ampl_l 0.24 NA   NA
D_overshoot_area_l 300.000m NA   NA
D_overshoot_area_h 300.000m NA   NA
[Receiver Thresholds]
Vth = 791.000mV
Vth_min = 751.000mV
Vth_max = 830.000mV
Vinh_ac = 68.000mV
Vinh_dc = 68.000mV
Vinl_ac = -68.000mV
Vinl_dc = -68.000mV
Tslew_ac = 5.000ns
Threshold_sensitivity = 0.5
Reference_supply Power_clamp_ref
[Temperature Range]   25.000   125.000   -40.000
[Voltage Range]   1.200V   1.140V   1.260V
[GND Clamp Reference]   0.00V   0.00V   0.00V
[C Comp Corner]
| variable   typ   min   max
C_comp 1.968pF   1.724pF   2.024pF
C_comp_pullup 960.943fF   809.272fF   985.834fF
C_comp_pulldown 863.816fF   819.972fF   885.457fF
[POWER Clamp Reference]   1.200V   1.140V   1.260V
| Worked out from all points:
|   GND clamp passes 1 mA (typ) near -0.24 V on its own axis
|   POWER clamp passes 1 mA (typ) near -0.39 V on its own axis
[GND Clamp]
-1.184V   -307.2mA   -361.3mA   -283.4mA
-1.069V   -70.98mA   -115.4mA   -53.13mA
-1.031V   -38.73mA   -68.75mA   -31.82mA
-992.7mV  -23.28mA   -39.39mA   -23.78mA
-954.6mV  -16.34mA   -22.75mA   -20.19mA
-916.4mV  -12.91mA   -13.86mA   -17.87mA
-840mV    -9.16mA    -6.438mA   -14.04mA
-649.1mV  -2.7mA     -818uA     -5.614mA
-420mV    1.32mA     1.59mA     464uA
1.145V    313nA      86.64uA    18.86nA
1.26V     1.071mA    2.077mA    22.08nA
2.367V    20.93mA    21.31mA    20.72mA
[Power Clamp]
-1.167V   159mA      195.3mA    141.9mA
-1.091V   81.24mA    116.8mA    65.1mA
-1.053V   52.46mA    84.54mA    40.2mA
-1.015V   32.59mA    58.3mA     25.87mA
-976.4mV  21.11mA    38.72mA    19.21mA
-938.2mV  15.32mA    25.5mA     16.18mA
-900mV    12.43mA    17.35mA    14.43mA
-785.5mV  8.55mA     8.121mA    10.62mA
-441.8mV  1.627mA    1.579mA    2.033mA
16.36mV   -298.8uA   -325.4uA   -310.6uA
856.4mV   -13.68mA   -13.92mA   -13.24mA
2.384V    -23.68mA   -32.57mA   -17.83mA
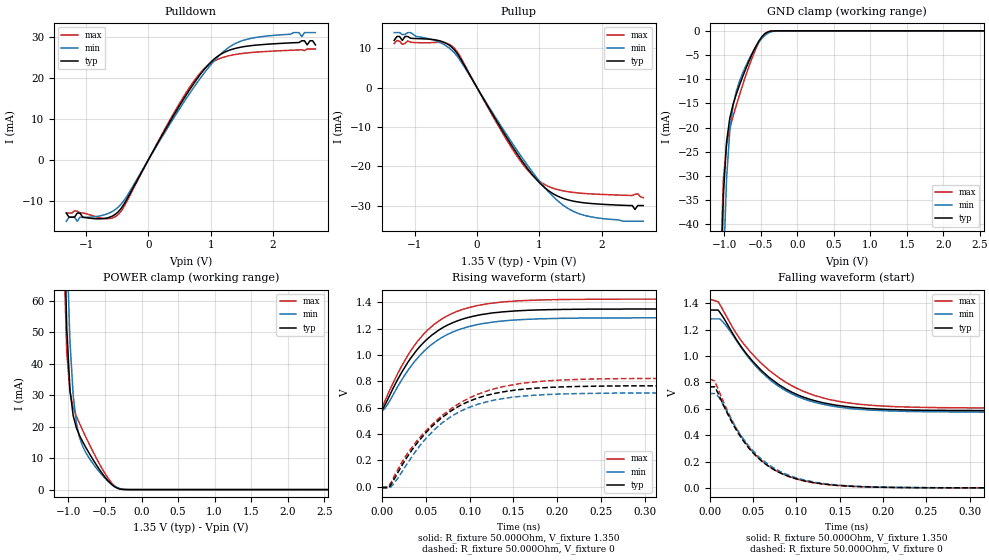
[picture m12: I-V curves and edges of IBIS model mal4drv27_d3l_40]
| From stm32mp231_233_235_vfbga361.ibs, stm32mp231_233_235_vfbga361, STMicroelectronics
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[Model] mal4drv27_d3l_40
Model_type   I/O
Polarity   Non-Inverting
Enable   Active-High
C_comp   1.684pF   1.663pF   1.711pF
C_comp_pullup   812.531fF   800.254fF   826.800fF
C_comp_pulldown   769.496fF   756.297fF   787.425fF
Vinh = 805.000mV
Vinl = 545.000mV
Vmeas = 675.000mV
Vref = 675.000mV
Rref = 50Ohms
Cref = 0pF
[Model Spec]
Vinh   805.000mV   772.000mV   855.000mV
Vinl   545.000mV   512.000mV   595.000mV
Vmeas   675.000mV   642.000mV   725.000mV
Vref   675.000mV   642.000mV   725.000mV
D_overshoot_ampl_h 0.4 NA   NA
D_overshoot_ampl_l 0.4 NA   NA
D_overshoot_area_l 110.000m NA   NA
D_overshoot_area_h 110.000m NA   NA
[Temperature Range]   25.000   125.000   -40.000
[Voltage Range]   1.350V   1.283V   1.425V
[GND Clamp Reference]   0.00V   0.00V   0.00V
[C Comp Corner]
| variable   typ   min   max
C_comp   1.684pF   1.663pF   1.711pF
C_comp_pullup   812.531fF   800.254fF   826.800fF
C_comp_pulldown   769.496fF   756.297fF   787.425fF
[Pulldown Reference]   0.00V   0.00V   0.00V
[POWER Clamp Reference]   1.350V   1.283V   1.425V
[Pullup Reference]   1.350V   1.283V   1.425V
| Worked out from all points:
|   slope of the pulldown table from 0 to 0.203 V, typ, clamps not added: 36.8 ohm
|   slope of the pullup table from 0 to 0.203 V, typ, clamps not added: 36.7 ohm
|   GND clamp passes 1 mA (typ) near -0.47 V on its own axis
|   POWER clamp passes 1 mA (typ) near -0.37 V on its own axis
|   rising waveform, R_fixture 50.000Ohm, V_fixture 1.350: 20-80 % time 54.5ps typ, 56.1ps min, 54ps max; typ from 0.58 V to 1.35 V
|   rising waveform, R_fixture 50.000Ohm, V_fixture 0: 20-80 % time 66.2ps typ, 63ps min, 74.3ps max; typ from -0.009 V to 0.767 V
|   falling waveform, R_fixture 50.000Ohm, V_fixture 1.350: 20-80 % time 67ps typ, 65.1ps min, 73.6ps max; typ from 1.35 V to 0.586 V
|   falling waveform, R_fixture 50.000Ohm, V_fixture 0: 20-80 % time 53.4ps typ, 55.4ps min, 52.7ps max; typ from 0.767 V to 0 V
[GND Clamp]
-1.318V   -672mA     -638mA     -661.1mA
-1.054V   -60.41mA   -84.99mA   -50.75mA
-1.011V   -34.02mA   -49.92mA   -30.84mA
-966.7mV  -22.91mA   -30.54mA   -23.58mA
-922.7mV  -18.04mA   -20.68mA   -20.16mA
-878.8mV  -15.25mA   -15.56mA   -17.69mA
-834.8mV  -13.14mA   -12.55mA   -15.44mA
-747mV    -9.486mA   -8.743mA   -11.21mA
-615.2mV  -4.709mA   -4.591mA   -5.504mA
-439.4mV  -562.2uA   -889.5uA   -546.1uA
-219.7mV  -954.1nA   -9.356uA   -215nA
2.68V     18.98nA    945nA      23.53nA
[Power Clamp]
-1.33V    889mA      842.2mA    872.8mA
-1.067V   94.44mA    130.9mA    77.96mA
-1.023V   51.04mA    78.45mA    43.53mA
-978.8mV  31.54mA    46.94mA    31.01mA
-934.8mV  23.45mA    29.85mA    26.15mA
-890.9mV  19.58mA    21.13mA    23.3mA
-847mV    17.11mA    16.47mA    20.93mA
-671.2mV  9.815mA    8.474mA    12.37mA
-495.5mV  3.823mA    3.529mA    4.955mA
-363.6mV  819.5uA    1.024mA    1.072mA
-187.9mV  4.227uA    28.6uA     2.566uA
2.668V    -29.12nA   -796.8nA   -15.73nA
[Pulldown]
-1.318V   -13mA      -15mA      -13mA
-1.274V   -14mA      -14mA      -13mA
-1.099V   -13mA      -14mA      -12.93mA
-790.9mV  -14.4mA    -13.72mA   -14.09mA
-483.3mV  -12.68mA   -11.53mA   -13.34mA
615.2mV   15.99mA    15.1mA     16.59mA
878.8mV   21.7mA     20.8mA     21.93mA
1.142V    25.54mA    25.5mA     24.65mA
1.582V    27.68mA    29.36mA    26.03mA
2.329V    28.52mA    31mA       26.71mA
2.461V    29mA       30mA       26.8mA
2.68V     28mA       31mA       27mA
[Pullup]
-1.33V    12mA       14mA       11.19mA
-1.286V   13mA       14mA       12mA
-1.199V   12mA       13.48mA    11mA
-1.155V   13mA       13.53mA    11.26mA
-671.2mV  12.14mA    11.94mA    11.48mA
-363.6mV  9.62mA     8.838mA    10.03mA
647mV     -16.88mA   -16.05mA   -17.54mA
910.6mV   -22.58mA   -21.91mA   -22.61mA
1.174V    -26.51mA   -26.94mA   -25.32mA
1.702V    -29.27mA   -32.4mA    -26.9mA
2.536V    -31mA      -34mA      -27.12mA
2.668V    -30mA      -34mA      -28mA
[Ramp]
R_load=50.000Ohm
dV/dt_r   459.300mV/61.000ps  425.999mV/60.500ps  492.600mV/65.000ps
dV/dt_f   459.300mV/61.000ps  425.999mV/61.500ps  492.600mV/64.500ps
[Rising waveform]
R_fixture=50.000Ohm
V_fixture=1.350
V_fixture_min=1.283
V_fixture_max=1.425
0s        580mV      571mV      597mV
6ps       651mV      617mV      686mV
27ps      916mV      855mV      967mV
46ps      1.083V     1.015V     1.146V
58ps      1.156V     1.086V     1.224V
73ps      1.221V     1.15V      1.292V
101ps     1.29V      1.219V     1.364V
138ps     1.328V     1.259V     1.404V
194ps     1.345V     1.278V     1.421V
500ps     1.35V      1.283V     1.425V
[Rising waveform]
R_fixture=50.000Ohm
V_fixture=0
0s        -9.009mV   -5.078mV   -624.6uV
8ps       -9.009mV   -5.078mV   -624.6uV
11ps      20.7mV     1.595mV    36.45mV
35ps      284mV      234mV      305mV
51ps      415mV      371mV      430mV
67ps      517mV      474mV      531mV
99ps      647mV      601mV      671mV
136ps     717mV      667mV      757mV
231ps     762mV      708mV      817mV
508ps     767mV      712mV      823mV
[Falling waveform]
R_fixture=50.000Ohm
V_fixture=1.350
V_fixture_min=1.283
V_fixture_max=1.425
0s        1.35V      1.283V     1.433V
10ps      1.35V      1.283V     1.413V
13ps      1.323V     1.277V     1.38V
38ps      1.058V     1.051V     1.105V
67ps      848mV      835mV      902mV
98ps      717mV      703mV      765mV
137ps     638mV      626mV      672mV
173ps     608mV      596mV      634mV
236ps     590mV      579mV      612mV
510ps     586mV      575mV      606mV
[Falling waveform]
R_fixture=50.000Ohm
V_fixture=0
0s        767mV      716mV      827mV
6ps       767mV      716mV      811mV
9ps       730mV      703mV      763mV
30ps      449mV      462mV      463mV
51ps      260mV      275mV      265mV
76ps      132mV      143mV      133mV
109ps     53.19mV    59.93mV    52.6mV
141ps     22.06mV    25.5mV     21.31mV
199ps     4.365mV    5.367mV    3.975mV
506ps     228nV      4.999uV    85.4nV
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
